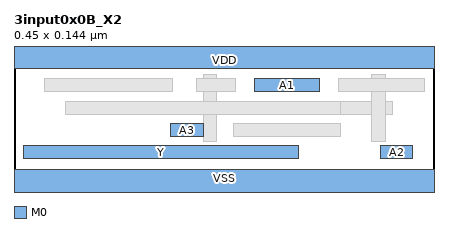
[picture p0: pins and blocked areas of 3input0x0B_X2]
MACRO 3input0x0B_X2
  CLASS CORE ;
  ORIGIN 0 0 ;
  FOREIGN 3input0x0B_X2 0 0 ;
  SIZE 0.4500 BY 0.1440 ;
  SYMMETRY X Y ;
  SITE coresite ;
  PIN A1
    DIRECTION INPUT ;
    USE SIGNAL ;
    PORT
      LAYER M0 ;
        RECT 0.2580 0.1010 0.3270 0.1150 ;
    END
  END A1
  PIN A2
    DIRECTION INPUT ;
    USE SIGNAL ;
    PORT
      LAYER M0 ;
        RECT 0.3930 0.0290 0.4275 0.0430 ;
    END
  END A2
  PIN A3
    DIRECTION INPUT ;
    USE SIGNAL ;
    PORT
      LAYER M0 ;
        RECT 0.1680 0.0530 0.2025 0.0670 ;
    END
  END A3
  PIN Y
    DIRECTION OUTPUT ;
    USE SIGNAL ;
    PORT
      LAYER M0 ;
        RECT 0.0105 0.0290 0.3045 0.0430 ;
    END
  END Y
  PIN VDD
    DIRECTION INOUT ;
    USE POWER ;
    SHAPE ABUTMENT ;
    PORT
      LAYER M0 ;
        RECT 0.0000 0.1260 0.4500 0.1620 ;
    END
  END VDD
  PIN VSS
    DIRECTION INOUT ;
    USE GROUND ;
    SHAPE ABUTMENT ;
    PORT
      LAYER M0 ;
        RECT 0.0000 -0.0180 0.4500 0.0180 ;
    END
  END VSS
  OBS
    LAYER M2 ;
      RECT 0.1980 0.0770 0.4050 0.0910 ;
    LAYER V1 ;
      RECT 0.2030 0.0770 0.2170 0.0910 ;
      RECT 0.3830 0.0770 0.3970 0.0910 ;
    LAYER M1 ;
      RECT 0.2025 0.0480 0.2175 0.1200 ;
      RECT 0.3825 0.0480 0.3975 0.1200 ;
    LAYER V0 ;
      RECT 0.2030 0.1010 0.2170 0.1150 ;
      RECT 0.3830 0.1010 0.3970 0.1150 ;
    LAYER M0 ;
      RECT 0.2355 0.0530 0.3495 0.0670 ;
      RECT 0.0555 0.0770 0.3495 0.0910 ;
      RECT 0.0330 0.1010 0.1695 0.1150 ;
      RECT 0.1950 0.1010 0.2370 0.1150 ;
      RECT 0.3480 0.1010 0.4395 0.1150 ;
  END
END 3input0x0B_X2
